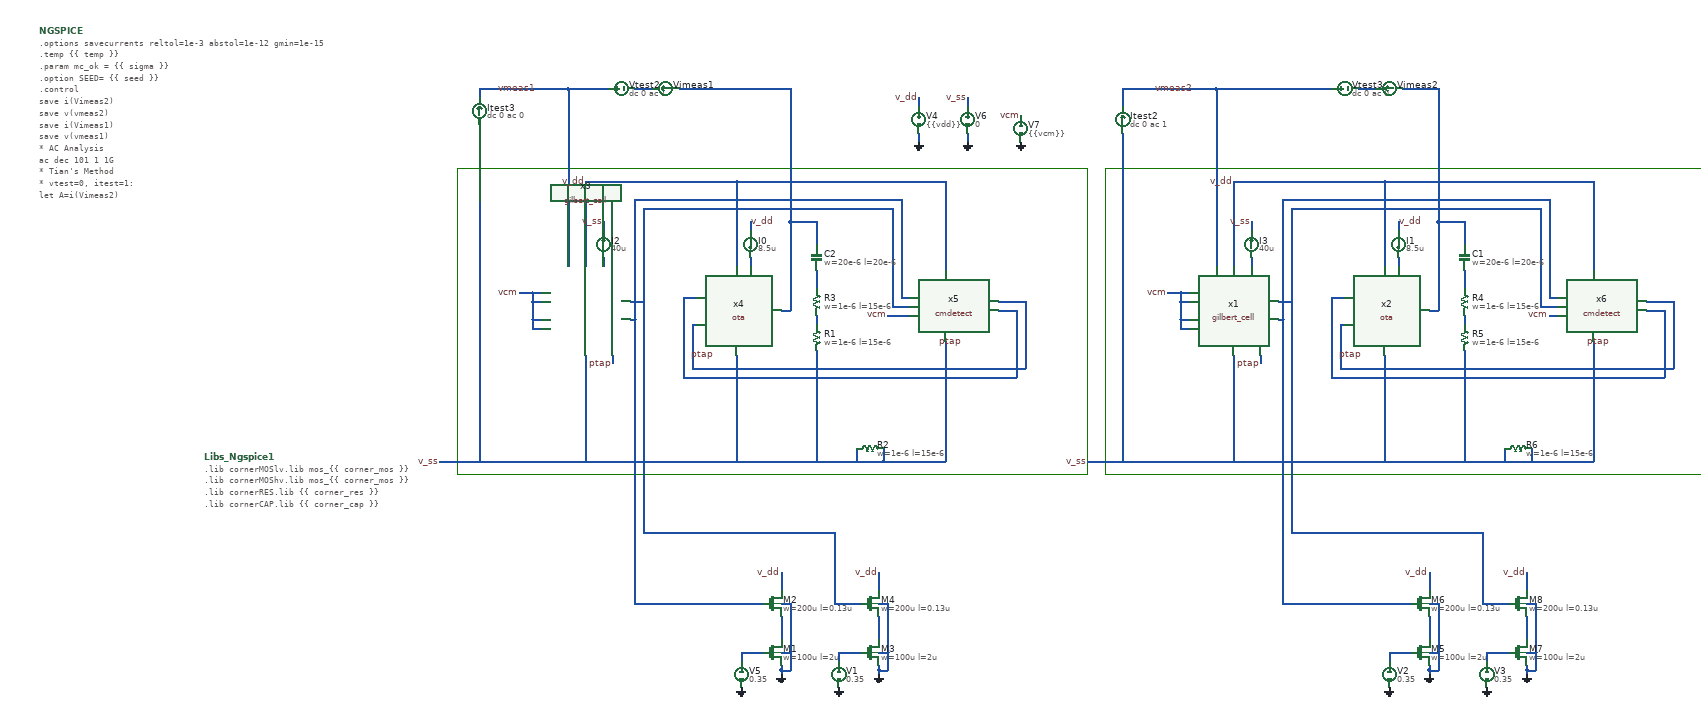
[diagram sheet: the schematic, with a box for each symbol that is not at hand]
v {xschem version=3.4.8RC file_version=1.3}
G {}
K {}
V {}
S {}
F {}
E {}
P 4 5 510 -780 1930 -780 1930 -90 510 -90 510 -780 {dash = 4}
P 4 5 1970 -780 3390 -780 3390 -90 1970 -90 1970 -780 {dash = 4}
N 910 -960 950 -960 {lab=#net1}
N 1010 -960 1260 -960 {lab=#net2}
N 560 -960 760 -960 {lab=vmeas1}
N 560 -960 560 -940 {lab=vmeas1}
N 2540 -960 2580 -960 {lab=#net3}
N 680 -480 700 -480 {lab=vcm}
N 680 -440 700 -440 {lab=vcm}
N 680 -420 700 -420 {lab=vcm}
N 1170 -580 1170 -560 {lab=#net4}
N 800 -360 800 -120 {lab=v_ss}
N 1040 -430 1050 -430 {lab=#net5}
N 1040 -430 1040 -330 {lab=#net5}
N 1020 -490 1020 -310 {lab=#net6}
N 1020 -490 1050 -490 {lab=#net6}
N 800 -750 800 -560 {lab=v_dd}
N 1140 -750 1140 -560 {lab=v_dd}
N 800 -750 1140 -750 {lab=v_dd}
N 1240 -460 1260 -460 {lab=#net2}
N 1260 -660 1260 -460 {lab=#net2}
N 900 -480 930 -480 {lab=#net7}
N 860 -360 860 -340 {lab=ptap}
N 910 -710 910 -440 {lab=#net8}
N 900 -440 910 -440 {lab=#net8}
N 1140 -360 1140 -120 {lab=v_ss}
N 800 -120 1140 -120 {lab=v_ss}
N 1320 -660 1320 -610 {lab=#net2}
N 1260 -660 1320 -660 {lab=#net2}
N 1140 -120 1320 -120 {lab=v_ss}
N 1320 -550 1320 -510 {lab=#net9}
N 1320 -450 1320 -430 {lab=#net10}
N 1320 -370 1320 -120 {lab=v_ss}
N 1610 -390 1610 -120 {lab=v_ss}
N 1470 -120 1610 -120 {lab=v_ss}
N 1610 -750 1610 -550 {lab=v_dd}
N 1140 -750 1610 -750 {lab=v_dd}
N 1730 -480 1790 -480 {lab=#net5}
N 1790 -480 1790 -330 {lab=#net5}
N 1040 -330 1790 -330 {lab=#net5}
N 1730 -460 1770 -460 {lab=#net6}
N 1770 -460 1770 -310 {lab=#net6}
N 1020 -310 1770 -310 {lab=#net6}
N 910 -710 1510 -710 {lab=#net8}
N 1510 -710 1510 -490 {lab=#net8}
N 1510 -490 1530 -490 {lab=#net8}
N 1490 -470 1530 -470 {lab=#net7}
N 1490 -690 1490 -470 {lab=#net7}
N 930 -690 1490 -690 {lab=#net7}
N 1410 -150 1410 -120 {lab=v_ss}
N 1320 -120 1410 -120 {lab=v_ss}
N 1470 -150 1470 -120 {lab=v_ss}
N 1410 -120 1470 -120 {lab=v_ss}
N 680 -500 700 -500 {lab=vcm}
N 680 -500 680 -480 {lab=vcm}
N 650 -500 680 -500 {lab=vcm}
N 680 -480 680 -440 {lab=vcm}
N 680 -440 680 -420 {lab=vcm}
N 760 -960 760 -560 {lab=vmeas1}
N 1260 -960 1260 -660 {lab=#net2}
N 760 -960 850 -960 {lab=vmeas1}
N 560 -890 560 -120 {lab=v_ss}
N 560 -120 800 -120 {lab=v_ss}
N 470 -120 560 -120 {lab=v_ss}
N 2140 -480 2160 -480 {lab=vcm}
N 2140 -440 2160 -440 {lab=vcm}
N 2140 -420 2160 -420 {lab=vcm}
N 2630 -580 2630 -560 {lab=#net11}
N 2260 -360 2260 -120 {lab=v_ss}
N 2500 -430 2510 -430 {lab=#net12}
N 2500 -430 2500 -330 {lab=#net12}
N 2480 -490 2480 -310 {lab=#net13}
N 2480 -490 2510 -490 {lab=#net13}
N 2260 -750 2260 -560 {lab=v_dd}
N 2600 -750 2600 -560 {lab=v_dd}
N 2260 -750 2600 -750 {lab=v_dd}
N 2700 -460 2720 -460 {lab=#net14}
N 2720 -660 2720 -460 {lab=#net14}
N 2320 -360 2320 -340 {lab=ptap}
N 2390 -690 2390 -480 {lab=#net15}
N 2370 -710 2370 -440 {lab=#net16}
N 2360 -440 2370 -440 {lab=#net16}
N 2600 -360 2600 -120 {lab=v_ss}
N 2260 -120 2600 -120 {lab=v_ss}
N 2780 -660 2780 -610 {lab=#net14}
N 2720 -660 2780 -660 {lab=#net14}
N 2600 -120 2780 -120 {lab=v_ss}
N 2780 -550 2780 -510 {lab=#net17}
N 2780 -450 2780 -430 {lab=#net18}
N 2780 -370 2780 -120 {lab=v_ss}
N 2970 -450 2990 -450 {lab=vcm}
N 3070 -390 3070 -120 {lab=v_ss}
N 2930 -120 3070 -120 {lab=v_ss}
N 3070 -750 3070 -550 {lab=v_dd}
N 2600 -750 3070 -750 {lab=v_dd}
N 3190 -480 3250 -480 {lab=#net12}
N 3250 -480 3250 -330 {lab=#net12}
N 2500 -330 3250 -330 {lab=#net12}
N 3190 -460 3230 -460 {lab=#net13}
N 3230 -460 3230 -310 {lab=#net13}
N 2480 -310 3230 -310 {lab=#net13}
N 2370 -710 2970 -710 {lab=#net16}
N 2970 -710 2970 -490 {lab=#net16}
N 2970 -490 2990 -490 {lab=#net16}
N 2950 -470 2990 -470 {lab=#net15}
N 2950 -690 2950 -470 {lab=#net15}
N 2390 -690 2950 -690 {lab=#net15}
N 2870 -150 2870 -120 {lab=v_ss}
N 2780 -120 2870 -120 {lab=v_ss}
N 2930 -150 2930 -120 {lab=v_ss}
N 2870 -120 2930 -120 {lab=v_ss}
N 2140 -500 2160 -500 {lab=vcm}
N 2140 -500 2140 -480 {lab=vcm}
N 2110 -500 2140 -500 {lab=vcm}
N 2140 -480 2140 -440 {lab=vcm}
N 2140 -440 2140 -420 {lab=vcm}
N 2010 -120 2260 -120 {lab=v_ss}
N 2720 -960 2720 -660 {lab=#net14}
N 2640 -960 2720 -960 {lab=#net14}
N 2220 -960 2220 -560 {lab=vmeas2}
N 2220 -960 2480 -960 {lab=vmeas2}
N 2010 -960 2220 -960 {lab=vmeas2}
N 2010 -960 2010 -920 {lab=vmeas2}
N 2010 -860 2010 -120 {lab=v_ss}
N 1930 -120 2010 -120 {lab=v_ss}
N 1480 -450 1530 -450 {lab=vcm}
N 1170 -660 1170 -640 {lab=v_dd}
N 840 -660 840 -640 {lab=v_ss}
N 840 -580 840 -560 {lab=#net19}
N 2630 -660 2630 -640 {lab=v_dd}
N 2300 -660 2300 -640 {lab=v_ss}
N 2300 -580 2300 -560 {lab=#net20}
N 910 -440 910 200 {lab=#net8}
N 2370 -440 2370 200 {lab=#net16}
N 2360 -480 2390 -480 {lab=#net15}
N 1240 350 1240 360 {lab=GND}
N 1240 310 1260 310 {lab=GND}
N 1260 310 1260 350 {lab=GND}
N 1240 350 1260 350 {lab=GND}
N 1240 340 1240 350 {lab=GND}
N 1240 200 1260 200 {lab=GND}
N 1240 230 1240 280 {lab=#net21}
N 1150 310 1150 330 {lab=#net22}
N 1150 310 1200 310 {lab=#net22}
N 1240 130 1240 170 {lab=v_dd}
N 1260 200 1260 310 {lab=GND}
N 1460 350 1460 360 {lab=GND}
N 1460 310 1480 310 {lab=GND}
N 1480 310 1480 350 {lab=GND}
N 1460 350 1480 350 {lab=GND}
N 1460 340 1460 350 {lab=GND}
N 1460 200 1480 200 {lab=GND}
N 1460 230 1460 280 {lab=#net23}
N 1370 310 1370 330 {lab=#net24}
N 1370 310 1420 310 {lab=#net24}
N 1460 130 1460 170 {lab=v_dd}
N 1480 200 1480 310 {lab=GND}
N 910 200 1200 200 {lab=#net8}
N 1360 200 1420 200 {lab=#net7}
N 1360 40 1360 200 {lab=#net7}
N 930 40 1360 40 {lab=#net7}
N 930 -480 930 40 {lab=#net7}
N 930 -690 930 -480 {lab=#net7}
N 2700 350 2700 360 {lab=GND}
N 2700 310 2720 310 {lab=GND}
N 2720 310 2720 350 {lab=GND}
N 2700 350 2720 350 {lab=GND}
N 2700 340 2700 350 {lab=GND}
N 2700 200 2720 200 {lab=GND}
N 2700 230 2700 280 {lab=#net25}
N 2610 310 2610 330 {lab=#net26}
N 2610 310 2660 310 {lab=#net26}
N 2700 130 2700 170 {lab=v_dd}
N 2720 200 2720 310 {lab=GND}
N 2920 350 2920 360 {lab=GND}
N 2920 310 2940 310 {lab=GND}
N 2940 310 2940 350 {lab=GND}
N 2920 350 2940 350 {lab=GND}
N 2920 340 2920 350 {lab=GND}
N 2920 200 2940 200 {lab=GND}
N 2920 230 2920 280 {lab=#net27}
N 2830 310 2830 330 {lab=#net28}
N 2830 310 2880 310 {lab=#net28}
N 2920 130 2920 170 {lab=v_dd}
N 2940 200 2940 310 {lab=GND}
N 2370 200 2660 200 {lab=#net16}
N 2820 200 2880 200 {lab=#net15}
N 2820 40 2820 200 {lab=#net15}
N 2390 40 2820 40 {lab=#net15}
N 2390 -480 2390 40 {lab=#net15}
N 1550 -940 1550 -920 {lab=v_dd}
N 1550 -860 1550 -840 {lab=GND}
N 1660 -940 1660 -920 {lab=v_ss}
N 1660 -860 1660 -840 {lab=GND}
C {devices/code_shown.sym} -430 -1090 0 0 {name=NGSPICE
only_toplevel=true
value="
.options savecurrents reltol=1e-3 abstol=1e-12 gmin=1e-15
.temp \{\{ temp \}\}
.param mc_ok = \{\{ sigma \}\}
.option SEED= \{\{ seed \}\}
.control
save i(Vimeas2)
save v(vmeas2)
save i(Vimeas1)
save v(vmeas1)

* AC Analysis
ac dec 101 1 1G

* Tian's Method
* vtest=0, itest=1:
let A=i(Vimeas2)
let C=v(vmeas2)

* vtest=1, itest=0:
let B=i(Vimeas1)
let D=v(vmeas1)
let ttian=(A*D-B*C-A)/(2*(B*C-A*D)+A-D+1)

let gain = db(ttian)
let phase = 180/pi*cphase(ttian)

* 1. Finde die 0dB Grenzfrequenz (Transitfrequenz)
meas ac cutoff when gain=0 fall=1

* 2. Finde das absolute Minimum der Phase vom Start der AC-Analyse bis zur Grenzfrequenz.
* (Wenn 'FROM' weggelassen wird, startet ngspice automatisch bei der niedrigsten Frequenz)
meas ac min_phase MIN phase TO=cutoff

* 3. Berechne die Worst-Case Phasenreserve basierend auf diesem Minimum
let phase_margin=180 + min_phase

echo MY_DATA:$&phase_margin

*quit
.endc
"}
C {devices/title.sym} -170 70 0 0 {name=l5 author="Santiago Hofwimmer | IICQC"}
C {lab_pin.sym} 1550 -940 0 0 {name=p2 sig_type=std_logic lab=v_dd
value=0.75}
C {lab_pin.sym} 1660 -940 0 0 {name=p1 sig_type=std_logic lab=v_ss}
C {lab_pin.sym} 470 -120 0 0 {name=p20 sig_type=std_logic lab=v_ss}
C {isource.sym} 560 -910 2 1 {name=Itest3 value="dc 0 ac 0"}
C {devices/vsource.sym} 880 -960 3 0 {name=Vtest2 value="dc 0 ac 1"}
C {lab_wire.sym} 600 -960 2 0 {name=p24 sig_type=std_logic lab=vmeas1}
C {ammeter.sym} 980 -960 1 0 {name=Vimeas1 savecurrent=true spice_ignore=0}
C {isource.sym} 2010 -890 2 1 {name=Itest2 value="dc 0 ac 1"}
C {devices/vsource.sym} 2510 -960 3 0 {name=Vtest3 value="dc 0 ac 0"}
C {lab_wire.sym} 2080 -960 2 0 {name=p25 sig_type=std_logic lab=vmeas2}
C {ammeter.sym} 2610 -960 1 0 {name=Vimeas2 savecurrent=true spice_ignore=0}
C {lab_pin.sym} 1650 -390 3 0 {name=p18 sig_type=std_logic lab=ptap
}
C {lab_pin.sym} 860 -340 3 0 {name=p28 sig_type=std_logic lab=ptap
}
C {lab_pin.sym} 1090 -360 3 0 {name=p30 sig_type=std_logic lab=ptap}
C {lit_compac/sch/gilbert_cell/gilbert_cell.sym} 800 -460 0 0 {name=x3}
C {lit_compac/sch/ota/ota.sym} 1140 -460 0 0 {name=x4}
C {sg13g2_pr/cap_cmim.sym} 1320 -580 0 0 {name=C2
model=cap_cmim
w=20e-6
l=20e-6
m=1
spiceprefix=X
}
C {sg13g2_pr/rppd.sym} 1320 -480 0 0 {name=R3
w=1e-6
l=15e-6
model=rppd
body=ptap
spiceprefix=X
b=0
m=1
}
C {sg13g2_pr/rppd.sym} 1320 -400 0 0 {name=R1
w=1e-6
l=15e-6
model=rppd
body=ptap
spiceprefix=X
b=0
m=1
}
C {lit_compac/sch/cmdetect/cmdetect.sym} 1550 -410 0 0 {name=x5}
C {sg13g2_pr/rppd.sym} 1440 -150 3 0 {name=R2
w=1e-6
l=15e-6
model=rppd
body=ptap
spiceprefix=X
b=0
m=1
}
C {lab_wire.sym} 650 -500 0 0 {name=p3 sig_type=std_logic lab=vcm}
C {lab_pin.sym} 800 -750 0 0 {name=p5 sig_type=std_logic lab=v_dd}
C {lab_pin.sym} 1930 -120 0 0 {name=p6 sig_type=std_logic lab=v_ss}
C {lab_pin.sym} 3110 -390 3 0 {name=p16 sig_type=std_logic lab=ptap
}
C {lab_pin.sym} 2320 -340 3 0 {name=p19 sig_type=std_logic lab=ptap
}
C {lab_pin.sym} 2550 -360 3 0 {name=p22 sig_type=std_logic lab=ptap}
C {lit_compac/sch/gilbert_cell/gilbert_cell.sym} 2260 -460 0 0 {name=x1}
C {lit_compac/sch/ota/ota.sym} 2600 -460 0 0 {name=x2}
C {sg13g2_pr/cap_cmim.sym} 2780 -580 0 0 {name=C1
model=cap_cmim
w=20e-6
l=20e-6
m=1
spiceprefix=X
}
C {sg13g2_pr/rppd.sym} 2780 -480 0 0 {name=R4
w=1e-6
l=15e-6
model=rppd
body=ptap
spiceprefix=X
b=0
m=1
}
C {sg13g2_pr/rppd.sym} 2780 -400 0 0 {name=R5
w=1e-6
l=15e-6
model=rppd
body=ptap
spiceprefix=X
b=0
m=1
}
C {lit_compac/sch/cmdetect/cmdetect.sym} 3010 -410 0 0 {name=x6}
C {sg13g2_pr/rppd.sym} 2900 -150 3 0 {name=R6
w=1e-6
l=15e-6
model=rppd
body=ptap
spiceprefix=X
b=0
m=1
}
C {lab_wire.sym} 2110 -500 0 0 {name=p37 sig_type=std_logic lab=vcm}
C {lab_pin.sym} 2260 -750 0 0 {name=p38 sig_type=std_logic lab=v_dd}
C {lab_wire.sym} 1480 -450 0 0 {name=p4 sig_type=std_logic lab=vcm}
C {lab_wire.sym} 2970 -450 0 0 {name=p7 sig_type=std_logic lab=vcm}
C {isource.sym} 1170 -610 0 0 {name=I0 value=8.5u}
C {isource.sym} 840 -610 2 0 {name=I2 value=40u}
C {lab_pin.sym} 1170 -660 2 0 {name=p8 sig_type=std_logic lab=v_dd}
C {lab_pin.sym} 840 -660 1 0 {name=p10 sig_type=std_logic lab=v_ss}
C {isource.sym} 2630 -610 0 0 {name=I1 value=8.5u}
C {lab_pin.sym} 2630 -660 2 0 {name=p9 sig_type=std_logic lab=v_dd}
C {isource.sym} 2300 -610 2 0 {name=I3 value=40u}
C {lab_pin.sym} 2300 -660 1 0 {name=p11 sig_type=std_logic lab=v_ss}
C {sg13g2_pr/sg13_lv_nmos.sym} 1220 310 0 0 {name=M1
l=2u
w=100u
ng=20
m=1
model=sg13_lv_nmos
spiceprefix=X
}
C {sg13g2_pr/sg13_lv_nmos.sym} 1220 200 0 0 {name=M2
l=0.13u
w=200u
ng=20
m=1
model=sg13_lv_nmos
spiceprefix=X
}
C {gnd.sym} 1240 360 0 0 {name=l13 lab=GND}
C {vsource.sym} 1150 360 0 0 {name=V5 value=0.35 savecurrent=true}
C {gnd.sym} 1150 390 0 0 {name=l17 lab=GND}
C {sg13g2_pr/sg13_lv_nmos.sym} 1440 310 0 0 {name=M3
l=2u
w=100u
ng=20
m=1
model=sg13_lv_nmos
spiceprefix=X
}
C {sg13g2_pr/sg13_lv_nmos.sym} 1440 200 0 0 {name=M4
l=0.13u
w=200u
ng=20
m=1
model=sg13_lv_nmos
spiceprefix=X
}
C {gnd.sym} 1460 360 0 0 {name=l4 lab=GND}
C {vsource.sym} 1370 360 0 0 {name=V1 value=0.35 savecurrent=true}
C {gnd.sym} 1370 390 0 0 {name=l6 lab=GND}
C {lab_pin.sym} 1240 130 1 0 {name=p13 sig_type=std_logic lab=v_dd}
C {lab_pin.sym} 1460 130 1 0 {name=p15 sig_type=std_logic lab=v_dd}
C {sg13g2_pr/sg13_lv_nmos.sym} 2680 310 0 0 {name=M5
l=2u
w=100u
ng=20
m=1
model=sg13_lv_nmos
spiceprefix=X
}
C {sg13g2_pr/sg13_lv_nmos.sym} 2680 200 0 0 {name=M6
l=0.13u
w=200u
ng=20
m=1
model=sg13_lv_nmos
spiceprefix=X
}
C {gnd.sym} 2700 360 0 0 {name=l7 lab=GND}
C {vsource.sym} 2610 360 0 0 {name=V2 value=0.35 savecurrent=true}
C {gnd.sym} 2610 390 0 0 {name=l8 lab=GND}
C {sg13g2_pr/sg13_lv_nmos.sym} 2900 310 0 0 {name=M7
l=2u
w=100u
ng=20
m=1
model=sg13_lv_nmos
spiceprefix=X
}
C {sg13g2_pr/sg13_lv_nmos.sym} 2900 200 0 0 {name=M8
l=0.13u
w=200u
ng=20
m=1
model=sg13_lv_nmos
spiceprefix=X
}
C {gnd.sym} 2920 360 0 0 {name=l9 lab=GND}
C {vsource.sym} 2830 360 0 0 {name=V3 value=0.35 savecurrent=true}
C {gnd.sym} 2830 390 0 0 {name=l11 lab=GND}
C {lab_pin.sym} 2700 130 1 0 {name=p14 sig_type=std_logic lab=v_dd}
C {lab_pin.sym} 2920 130 1 0 {name=p17 sig_type=std_logic lab=v_dd}
C {vsource.sym} 1550 -890 0 0 {name=V4 value=\{\{vdd\}\} savecurrent=false}
C {gnd.sym} 1550 -840 0 0 {name=l1 lab=GND}
C {vsource.sym} 1660 -890 0 0 {name=V6 value=0 savecurrent=false}
C {gnd.sym} 1660 -840 0 0 {name=l3 lab=GND}
C {vsource.sym} 1780 -870 0 0 {name=V7 value=\{\{vcm\}\} savecurrent=true}
C {gnd.sym} 1780 -840 0 0 {name=l10 lab=GND}
C {lab_pin.sym} 1780 -900 1 0 {name=p21 sig_type=std_logic lab=vcm}
C {simulator_commands_shown.sym} -60 -130 0 0 {
name=Libs_Ngspice1
simulator=ngspice
only_toplevel=false
value="
.lib cornerMOSlv.lib mos_\{\{ corner_mos \}\}
.lib cornerMOShv.lib mos_\{\{ corner_mos \}\}
.lib cornerRES.lib \{\{ corner_res \}\}
.lib cornerCAP.lib \{\{ corner_cap \}\}
"
      }
